VERSION 5.7 ;
  NOWIREEXTENSIONATPIN ON ;
  DIVIDERCHAR "/" ;
  BUSBITCHARS "[]" ;
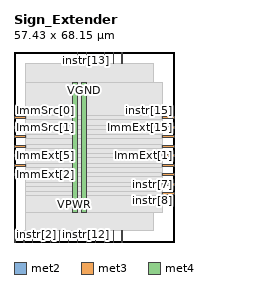
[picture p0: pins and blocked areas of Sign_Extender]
MACRO Sign_Extender
  CLASS BLOCK ;
  FOREIGN Sign_Extender ;
  ORIGIN 0.000 0.000 ;
  SIZE 57.430 BY 68.150 ;
  PIN ImmExt[0]
    DIRECTION OUTPUT ;
    USE SIGNAL ;
    ANTENNADIFFAREA 0.445500 ;
    PORT
      LAYER met2 ;
        RECT 32.290 64.150 32.570 68.150 ;
    END
  END ImmExt[0]
  PIN ImmExt[10]
    DIRECTION OUTPUT ;
    USE SIGNAL ;
    ANTENNADIFFAREA 0.445500 ;
    PORT
      LAYER met3 ;
        RECT 53.430 37.440 57.430 38.040 ;
    END
  END ImmExt[10]
  PIN ImmExt[11]
    DIRECTION OUTPUT ;
    USE SIGNAL ;
    ANTENNADIFFAREA 0.445500 ;
    PORT
      LAYER met2 ;
        RECT 19.410 0.000 19.690 4.000 ;
    END
  END ImmExt[11]
  PIN ImmExt[12]
    DIRECTION OUTPUT ;
    USE SIGNAL ;
    ANTENNADIFFAREA 0.445500 ;
    PORT
      LAYER met2 ;
        RECT 22.630 0.000 22.910 4.000 ;
    END
  END ImmExt[12]
  PIN ImmExt[13]
    DIRECTION OUTPUT ;
    USE SIGNAL ;
    ANTENNADIFFAREA 0.445500 ;
    PORT
      LAYER met2 ;
        RECT 22.630 64.150 22.910 68.150 ;
    END
  END ImmExt[13]
  PIN ImmExt[14]
    DIRECTION OUTPUT ;
    USE SIGNAL ;
    ANTENNADIFFAREA 0.445500 ;
    PORT
      LAYER met3 ;
        RECT 53.430 27.240 57.430 27.840 ;
    END
  END ImmExt[14]
  PIN ImmExt[15]
    DIRECTION OUTPUT ;
    USE SIGNAL ;
    ANTENNADIFFAREA 0.445500 ;
    PORT
      LAYER met3 ;
        RECT 53.430 40.840 57.430 41.440 ;
    END
  END ImmExt[15]
  PIN ImmExt[1]
    DIRECTION OUTPUT ;
    USE SIGNAL ;
    ANTENNADIFFAREA 0.445500 ;
    PORT
      LAYER met3 ;
        RECT 53.430 30.640 57.430 31.240 ;
    END
  END ImmExt[1]
  PIN ImmExt[2]
    DIRECTION OUTPUT ;
    USE SIGNAL ;
    ANTENNADIFFAREA 0.445500 ;
    PORT
      LAYER met3 ;
        RECT 0.000 23.840 4.000 24.440 ;
    END
  END ImmExt[2]
  PIN ImmExt[3]
    DIRECTION OUTPUT ;
    USE SIGNAL ;
    ANTENNADIFFAREA 0.445500 ;
    PORT
      LAYER met3 ;
        RECT 0.000 27.240 4.000 27.840 ;
    END
  END ImmExt[3]
  PIN ImmExt[4]
    DIRECTION OUTPUT ;
    USE SIGNAL ;
    ANTENNADIFFAREA 0.445500 ;
    PORT
      LAYER met3 ;
        RECT 0.000 37.440 4.000 38.040 ;
    END
  END ImmExt[4]
  PIN ImmExt[5]
    DIRECTION OUTPUT ;
    USE SIGNAL ;
    ANTENNADIFFAREA 0.445500 ;
    PORT
      LAYER met3 ;
        RECT 0.000 30.640 4.000 31.240 ;
    END
  END ImmExt[5]
  PIN ImmExt[6]
    DIRECTION OUTPUT ;
    USE SIGNAL ;
    ANTENNADIFFAREA 0.445500 ;
    PORT
      LAYER met2 ;
        RECT 38.730 0.000 39.010 4.000 ;
    END
  END ImmExt[6]
  PIN ImmExt[7]
    DIRECTION OUTPUT ;
    USE SIGNAL ;
    ANTENNADIFFAREA 0.445500 ;
    PORT
      LAYER met2 ;
        RECT 35.510 0.000 35.790 4.000 ;
    END
  END ImmExt[7]
  PIN ImmExt[8]
    DIRECTION OUTPUT ;
    USE SIGNAL ;
    ANTENNADIFFAREA 0.445500 ;
    PORT
      LAYER met2 ;
        RECT 32.290 0.000 32.570 4.000 ;
    END
  END ImmExt[8]
  PIN ImmExt[9]
    DIRECTION OUTPUT ;
    USE SIGNAL ;
    ANTENNADIFFAREA 0.445500 ;
    PORT
      LAYER met2 ;
        RECT 35.510 64.150 35.790 68.150 ;
    END
  END ImmExt[9]
  PIN ImmSrc[0]
    DIRECTION INPUT ;
    USE SIGNAL ;
    ANTENNAGATEAREA 0.196500 ;
    PORT
      LAYER met3 ;
        RECT 0.000 44.240 4.000 44.840 ;
    END
  END ImmSrc[0]
  PIN ImmSrc[1]
    DIRECTION INPUT ;
    USE SIGNAL ;
    ANTENNAGATEAREA 0.213000 ;
    PORT
      LAYER met3 ;
        RECT 0.000 40.840 4.000 41.440 ;
    END
  END ImmSrc[1]
  PIN VGND
    DIRECTION INOUT ;
    USE GROUND ;
    PORT
      LAYER met4 ;
        RECT 24.340 10.640 25.940 57.360 ;
    END
  END VGND
  PIN VPWR
    DIRECTION INOUT ;
    USE POWER ;
    PORT
      LAYER met4 ;
        RECT 21.040 10.640 22.640 57.360 ;
    END
  END VPWR
  PIN instr[0]
    DIRECTION INPUT ;
    USE SIGNAL ;
    PORT
      LAYER met2 ;
        RECT 0.090 0.000 0.370 4.000 ;
    END
  END instr[0]
  PIN instr[10]
    DIRECTION INPUT ;
    USE SIGNAL ;
    ANTENNAGATEAREA 0.196500 ;
    PORT
      LAYER met3 ;
        RECT 53.430 34.040 57.430 34.640 ;
    END
  END instr[10]
  PIN instr[11]
    DIRECTION INPUT ;
    USE SIGNAL ;
    ANTENNAGATEAREA 0.196500 ;
    PORT
      LAYER met2 ;
        RECT 29.070 0.000 29.350 4.000 ;
    END
  END instr[11]
  PIN instr[12]
    DIRECTION INPUT ;
    USE SIGNAL ;
    ANTENNAGATEAREA 0.196500 ;
    PORT
      LAYER met2 ;
        RECT 25.850 0.000 26.130 4.000 ;
    END
  END instr[12]
  PIN instr[13]
    DIRECTION INPUT ;
    USE SIGNAL ;
    ANTENNAGATEAREA 0.196500 ;
    PORT
      LAYER met2 ;
        RECT 25.850 64.150 26.130 68.150 ;
    END
  END instr[13]
  PIN instr[14]
    DIRECTION INPUT ;
    USE SIGNAL ;
    ANTENNAGATEAREA 0.196500 ;
    PORT
      LAYER met3 ;
        RECT 0.000 34.040 4.000 34.640 ;
    END
  END instr[14]
  PIN instr[15]
    DIRECTION INPUT ;
    USE SIGNAL ;
    ANTENNAGATEAREA 0.196500 ;
    PORT
      LAYER met3 ;
        RECT 53.430 44.240 57.430 44.840 ;
    END
  END instr[15]
  PIN instr[1]
    DIRECTION INPUT ;
    USE SIGNAL ;
    PORT
      LAYER met2 ;
        RECT 3.310 0.000 3.590 4.000 ;
    END
  END instr[1]
  PIN instr[2]
    DIRECTION INPUT ;
    USE SIGNAL ;
    PORT
      LAYER met2 ;
        RECT 6.530 0.000 6.810 4.000 ;
    END
  END instr[2]
  PIN instr[3]
    DIRECTION INPUT ;
    USE SIGNAL ;
    PORT
      LAYER met2 ;
        RECT 9.750 0.000 10.030 4.000 ;
    END
  END instr[3]
  PIN instr[4]
    DIRECTION INPUT ;
    USE SIGNAL ;
    PORT
      LAYER met2 ;
        RECT 12.970 0.000 13.250 4.000 ;
    END
  END instr[4]
  PIN instr[5]
    DIRECTION INPUT ;
    USE SIGNAL ;
    PORT
      LAYER met2 ;
        RECT 16.190 0.000 16.470 4.000 ;
    END
  END instr[5]
  PIN instr[6]
    DIRECTION INPUT ;
    USE SIGNAL ;
    ANTENNAGATEAREA 0.196500 ;
    PORT
      LAYER met3 ;
        RECT 53.430 23.840 57.430 24.440 ;
    END
  END instr[6]
  PIN instr[7]
    DIRECTION INPUT ;
    USE SIGNAL ;
    ANTENNAGATEAREA 0.196500 ;
    PORT
      LAYER met3 ;
        RECT 53.430 20.440 57.430 21.040 ;
    END
  END instr[7]
  PIN instr[8]
    DIRECTION INPUT ;
    USE SIGNAL ;
    ANTENNAGATEAREA 0.196500 ;
    PORT
      LAYER met3 ;
        RECT 53.430 17.040 57.430 17.640 ;
    END
  END instr[8]
  PIN instr[9]
    DIRECTION INPUT ;
    USE SIGNAL ;
    ANTENNAGATEAREA 0.196500 ;
    PORT
      LAYER met2 ;
        RECT 38.730 64.150 39.010 68.150 ;
    END
  END instr[9]
  OBS
      LAYER nwell ;
        RECT 5.330 10.795 51.710 57.310 ;
      LAYER li1 ;
        RECT 5.520 10.795 51.520 57.205 ;
      LAYER met1 ;
        RECT 4.210 10.640 51.520 57.360 ;
      LAYER met2 ;
        RECT 4.230 63.870 22.350 64.150 ;
        RECT 23.190 63.870 25.570 64.150 ;
        RECT 26.410 63.870 32.010 64.150 ;
        RECT 32.850 63.870 35.230 64.150 ;
        RECT 36.070 63.870 38.450 64.150 ;
        RECT 39.290 63.870 50.050 64.150 ;
        RECT 4.230 4.280 50.050 63.870 ;
        RECT 4.230 4.000 6.250 4.280 ;
        RECT 7.090 4.000 9.470 4.280 ;
        RECT 10.310 4.000 12.690 4.280 ;
        RECT 13.530 4.000 15.910 4.280 ;
        RECT 16.750 4.000 19.130 4.280 ;
        RECT 19.970 4.000 22.350 4.280 ;
        RECT 23.190 4.000 25.570 4.280 ;
        RECT 26.410 4.000 28.790 4.280 ;
        RECT 29.630 4.000 32.010 4.280 ;
        RECT 32.850 4.000 35.230 4.280 ;
        RECT 36.070 4.000 38.450 4.280 ;
        RECT 39.290 4.000 50.050 4.280 ;
      LAYER met3 ;
        RECT 3.990 45.240 53.430 57.285 ;
        RECT 4.400 43.840 53.030 45.240 ;
        RECT 3.990 41.840 53.430 43.840 ;
        RECT 4.400 40.440 53.030 41.840 ;
        RECT 3.990 38.440 53.430 40.440 ;
        RECT 4.400 37.040 53.030 38.440 ;
        RECT 3.990 35.040 53.430 37.040 ;
        RECT 4.400 33.640 53.030 35.040 ;
        RECT 3.990 31.640 53.430 33.640 ;
        RECT 4.400 30.240 53.030 31.640 ;
        RECT 3.990 28.240 53.430 30.240 ;
        RECT 4.400 26.840 53.030 28.240 ;
        RECT 3.990 24.840 53.430 26.840 ;
        RECT 4.400 23.440 53.030 24.840 ;
        RECT 3.990 21.440 53.430 23.440 ;
        RECT 3.990 20.040 53.030 21.440 ;
        RECT 3.990 18.040 53.430 20.040 ;
        RECT 3.990 16.640 53.030 18.040 ;
        RECT 3.990 10.715 53.430 16.640 ;
  END
END Sign_Extender
END LIBRARY

